VERSION 5.7 ;
  NOWIREEXTENSIONATPIN ON ;
  DIVIDERCHAR "/" ;
  BUSBITCHARS "[]" ;
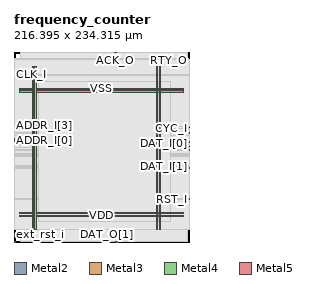
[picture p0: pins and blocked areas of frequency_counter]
MACRO frequency_counter
  CLASS BLOCK ;
  FOREIGN frequency_counter ;
  ORIGIN 0.000 0.000 ;
  SIZE 216.395 BY 234.315 ;
  PIN ACK_O
    DIRECTION OUTPUT ;
    USE SIGNAL ;
    ANTENNADIFFAREA 0.897600 ;
    PORT
      LAYER Metal2 ;
        RECT 125.440 233.755 126.000 234.315 ;
    END
  END ACK_O
  PIN ADDR_I[0]
    DIRECTION INPUT ;
    USE SIGNAL ;
    ANTENNAGATEAREA 0.396000 ;
    PORT
      LAYER Metal3 ;
        RECT 0.000 125.440 0.560 126.000 ;
    END
  END ADDR_I[0]
  PIN ADDR_I[1]
    DIRECTION INPUT ;
    USE SIGNAL ;
    ANTENNAGATEAREA 0.396000 ;
    PORT
      LAYER Metal3 ;
        RECT 0.000 126.560 0.560 127.120 ;
    END
  END ADDR_I[1]
  PIN ADDR_I[2]
    DIRECTION INPUT ;
    USE SIGNAL ;
    ANTENNAGATEAREA 0.396000 ;
    PORT
      LAYER Metal3 ;
        RECT 0.000 127.680 0.560 128.240 ;
    END
  END ADDR_I[2]
  PIN ADDR_I[3]
    DIRECTION INPUT ;
    USE SIGNAL ;
    ANTENNAGATEAREA 0.396000 ;
    PORT
      LAYER Metal3 ;
        RECT 0.000 133.280 0.560 133.840 ;
    END
  END ADDR_I[3]
  PIN ADDR_I[4]
    DIRECTION INPUT ;
    USE SIGNAL ;
    ANTENNAGATEAREA 0.396000 ;
    PORT
      LAYER Metal3 ;
        RECT 0.000 128.800 0.560 129.360 ;
    END
  END ADDR_I[4]
  PIN ADDR_I[5]
    DIRECTION INPUT ;
    USE SIGNAL ;
    ANTENNAGATEAREA 0.396000 ;
    PORT
      LAYER Metal3 ;
        RECT 0.000 132.160 0.560 132.720 ;
    END
  END ADDR_I[5]
  PIN ADDR_I[6]
    DIRECTION INPUT ;
    USE SIGNAL ;
    ANTENNAGATEAREA 0.396000 ;
    PORT
      LAYER Metal3 ;
        RECT 0.000 129.920 0.560 130.480 ;
    END
  END ADDR_I[6]
  PIN ADDR_I[7]
    DIRECTION INPUT ;
    USE SIGNAL ;
    ANTENNAGATEAREA 0.396000 ;
    PORT
      LAYER Metal3 ;
        RECT 0.000 131.040 0.560 131.600 ;
    END
  END ADDR_I[7]
  PIN CLK_I
    DIRECTION INPUT ;
    USE SIGNAL ;
    ANTENNAGATEAREA 4.738000 ;
    PORT
      LAYER Metal3 ;
        RECT 0.000 206.080 0.560 206.640 ;
    END
  END CLK_I
  PIN CYC_I
    DIRECTION INPUT ;
    USE SIGNAL ;
    ANTENNAGATEAREA 0.396000 ;
    PORT
      LAYER Metal3 ;
        RECT 215.835 140.000 216.395 140.560 ;
    END
  END CYC_I
  PIN DAT_I[0]
    DIRECTION INPUT ;
    USE SIGNAL ;
    ANTENNAGATEAREA 0.396000 ;
    PORT
      LAYER Metal3 ;
        RECT 215.835 131.040 216.395 131.600 ;
    END
  END DAT_I[0]
  PIN DAT_I[1]
    DIRECTION INPUT ;
    USE SIGNAL ;
    ANTENNAGATEAREA 0.396000 ;
    PORT
      LAYER Metal3 ;
        RECT 215.835 92.960 216.395 93.520 ;
    END
  END DAT_I[1]
  PIN DAT_I[2]
    DIRECTION INPUT ;
    USE SIGNAL ;
    ANTENNAGATEAREA 0.396000 ;
    PORT
      LAYER Metal3 ;
        RECT 215.835 94.080 216.395 94.640 ;
    END
  END DAT_I[2]
  PIN DAT_I[3]
    DIRECTION INPUT ;
    USE SIGNAL ;
    ANTENNAGATEAREA 0.396000 ;
    PORT
      LAYER Metal3 ;
        RECT 215.835 90.720 216.395 91.280 ;
    END
  END DAT_I[3]
  PIN DAT_I[4]
    DIRECTION INPUT ;
    USE SIGNAL ;
    ANTENNAGATEAREA 0.396000 ;
    PORT
      LAYER Metal3 ;
        RECT 215.835 117.600 216.395 118.160 ;
    END
  END DAT_I[4]
  PIN DAT_I[5]
    DIRECTION INPUT ;
    USE SIGNAL ;
    ANTENNAGATEAREA 0.396000 ;
    PORT
      LAYER Metal3 ;
        RECT 215.835 134.400 216.395 134.960 ;
    END
  END DAT_I[5]
  PIN DAT_I[6]
    DIRECTION INPUT ;
    USE SIGNAL ;
    ANTENNAGATEAREA 0.396000 ;
    PORT
      LAYER Metal3 ;
        RECT 215.835 120.960 216.395 121.520 ;
    END
  END DAT_I[6]
  PIN DAT_I[7]
    DIRECTION INPUT ;
    USE SIGNAL ;
    ANTENNAGATEAREA 0.396000 ;
    PORT
      LAYER Metal3 ;
        RECT 215.835 113.120 216.395 113.680 ;
    END
  END DAT_I[7]
  PIN DAT_O[0]
    DIRECTION OUTPUT ;
    USE SIGNAL ;
    ANTENNADIFFAREA 0.897600 ;
    PORT
      LAYER Metal3 ;
        RECT 215.835 116.480 216.395 117.040 ;
    END
  END DAT_O[0]
  PIN DAT_O[1]
    DIRECTION OUTPUT ;
    USE SIGNAL ;
    ANTENNADIFFAREA 0.897600 ;
    PORT
      LAYER Metal2 ;
        RECT 114.240 0.000 114.800 0.560 ;
    END
  END DAT_O[1]
  PIN DAT_O[2]
    DIRECTION OUTPUT ;
    USE SIGNAL ;
    ANTENNADIFFAREA 0.897600 ;
    PORT
      LAYER Metal2 ;
        RECT 127.680 0.000 128.240 0.560 ;
    END
  END DAT_O[2]
  PIN DAT_O[3]
    DIRECTION OUTPUT ;
    USE SIGNAL ;
    ANTENNADIFFAREA 0.897600 ;
    PORT
      LAYER Metal2 ;
        RECT 128.800 0.000 129.360 0.560 ;
    END
  END DAT_O[3]
  PIN DAT_O[4]
    DIRECTION OUTPUT ;
    USE SIGNAL ;
    ANTENNADIFFAREA 0.897600 ;
    PORT
      LAYER Metal3 ;
        RECT 215.835 105.280 216.395 105.840 ;
    END
  END DAT_O[4]
  PIN DAT_O[5]
    DIRECTION OUTPUT ;
    USE SIGNAL ;
    ANTENNADIFFAREA 0.897600 ;
    PORT
      LAYER Metal3 ;
        RECT 215.835 123.200 216.395 123.760 ;
    END
  END DAT_O[5]
  PIN DAT_O[6]
    DIRECTION OUTPUT ;
    USE SIGNAL ;
    ANTENNADIFFAREA 0.897600 ;
    PORT
      LAYER Metal3 ;
        RECT 215.835 108.640 216.395 109.200 ;
    END
  END DAT_O[6]
  PIN DAT_O[7]
    DIRECTION OUTPUT ;
    USE SIGNAL ;
    ANTENNADIFFAREA 0.897600 ;
    PORT
      LAYER Metal2 ;
        RECT 112.000 0.000 112.560 0.560 ;
    END
  END DAT_O[7]
  PIN ERR_O
    DIRECTION OUTPUT ;
    USE SIGNAL ;
    ANTENNADIFFAREA 0.897600 ;
    PORT
      LAYER Metal2 ;
        RECT 124.320 233.755 124.880 234.315 ;
    END
  END ERR_O
  PIN RST_I
    DIRECTION INPUT ;
    USE SIGNAL ;
    ANTENNAGATEAREA 0.396000 ;
    PORT
      LAYER Metal3 ;
        RECT 215.835 52.640 216.395 53.200 ;
    END
  END RST_I
  PIN RTY_O
    DIRECTION OUTPUT ;
    USE SIGNAL ;
    ANTENNADIFFAREA 0.360800 ;
    PORT
      LAYER Metal3 ;
        RECT 215.835 226.240 216.395 226.800 ;
    END
  END RTY_O
  PIN STB_I
    DIRECTION INPUT ;
    USE SIGNAL ;
    ANTENNAGATEAREA 0.396000 ;
    PORT
      LAYER Metal3 ;
        RECT 215.835 141.120 216.395 141.680 ;
    END
  END STB_I
  PIN VDD
    DIRECTION INOUT ;
    USE POWER ;
    PORT
      LAYER Metal4 ;
        RECT 22.240 15.380 23.840 215.900 ;
    END
    PORT
      LAYER Metal4 ;
        RECT 175.840 15.380 177.440 215.900 ;
    END
    PORT
      LAYER Metal5 ;
        RECT 6.720 31.530 209.440 33.130 ;
    END
    PORT
      LAYER Metal5 ;
        RECT 6.720 184.710 209.440 186.310 ;
    END
  END VDD
  PIN VSS
    DIRECTION INOUT ;
    USE GROUND ;
    PORT
      LAYER Metal4 ;
        RECT 25.540 15.380 27.140 215.900 ;
    END
    PORT
      LAYER Metal4 ;
        RECT 179.140 15.380 180.740 215.900 ;
    END
    PORT
      LAYER Metal5 ;
        RECT 6.720 34.830 209.440 36.430 ;
    END
    PORT
      LAYER Metal5 ;
        RECT 6.720 188.010 209.440 189.610 ;
    END
  END VSS
  PIN WE_I
    DIRECTION INPUT ;
    USE SIGNAL ;
    ANTENNAGATEAREA 0.396000 ;
    PORT
      LAYER Metal3 ;
        RECT 0.000 124.320 0.560 124.880 ;
    END
  END WE_I
  PIN ext_rst_i
    DIRECTION INPUT ;
    USE SIGNAL ;
    PORT
      LAYER Metal2 ;
        RECT 1.120 0.000 1.680 0.560 ;
    END
  END ext_rst_i
  PIN signal_input
    DIRECTION INPUT ;
    USE SIGNAL ;
    ANTENNAGATEAREA 0.396000 ;
    PORT
      LAYER Metal2 ;
        RECT 125.440 0.000 126.000 0.560 ;
    END
  END signal_input
  PIN trigger_signal_out
    DIRECTION OUTPUT ;
    USE SIGNAL ;
    ANTENNADIFFAREA 0.897600 ;
    PORT
      LAYER Metal3 ;
        RECT 215.835 225.120 216.395 225.680 ;
    END
  END trigger_signal_out
  OBS
      LAYER Nwell ;
        RECT 6.290 15.250 209.870 216.030 ;
      LAYER Metal1 ;
        RECT 6.720 15.380 209.440 215.900 ;
      LAYER Metal2 ;
        RECT 8.540 233.455 124.020 233.755 ;
        RECT 126.300 233.455 214.340 233.755 ;
        RECT 8.540 0.860 214.340 233.455 ;
        RECT 8.540 0.560 111.700 0.860 ;
        RECT 112.860 0.560 113.940 0.860 ;
        RECT 115.100 0.560 125.140 0.860 ;
        RECT 126.300 0.560 127.380 0.860 ;
        RECT 129.660 0.560 214.340 0.860 ;
      LAYER Metal3 ;
        RECT 0.560 224.820 215.535 226.660 ;
        RECT 0.560 206.940 216.255 224.820 ;
        RECT 0.860 205.780 216.255 206.940 ;
        RECT 0.560 141.980 216.255 205.780 ;
        RECT 0.560 139.700 215.535 141.980 ;
        RECT 0.560 135.260 216.255 139.700 ;
        RECT 0.560 134.140 215.535 135.260 ;
        RECT 0.860 134.100 215.535 134.140 ;
        RECT 0.860 131.900 216.255 134.100 ;
        RECT 0.860 130.740 215.535 131.900 ;
        RECT 0.860 124.060 216.255 130.740 ;
        RECT 0.860 124.020 215.535 124.060 ;
        RECT 0.560 122.900 215.535 124.020 ;
        RECT 0.560 121.820 216.255 122.900 ;
        RECT 0.560 120.660 215.535 121.820 ;
        RECT 0.560 118.460 216.255 120.660 ;
        RECT 0.560 116.180 215.535 118.460 ;
        RECT 0.560 113.980 216.255 116.180 ;
        RECT 0.560 112.820 215.535 113.980 ;
        RECT 0.560 109.500 216.255 112.820 ;
        RECT 0.560 108.340 215.535 109.500 ;
        RECT 0.560 106.140 216.255 108.340 ;
        RECT 0.560 104.980 215.535 106.140 ;
        RECT 0.560 94.940 216.255 104.980 ;
        RECT 0.560 92.660 215.535 94.940 ;
        RECT 0.560 91.580 216.255 92.660 ;
        RECT 0.560 90.420 215.535 91.580 ;
        RECT 0.560 53.500 216.255 90.420 ;
        RECT 0.560 52.340 215.535 53.500 ;
        RECT 0.560 15.540 216.255 52.340 ;
      LAYER Metal4 ;
        RECT 29.820 24.730 175.540 197.590 ;
        RECT 177.740 24.730 178.840 197.590 ;
        RECT 181.040 24.730 193.060 197.590 ;
  END
END frequency_counter
END LIBRARY

